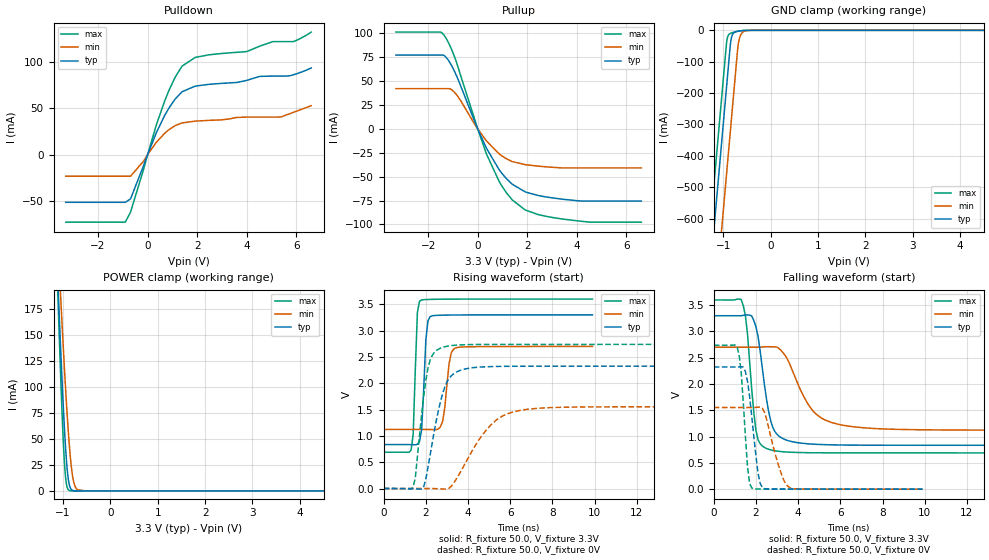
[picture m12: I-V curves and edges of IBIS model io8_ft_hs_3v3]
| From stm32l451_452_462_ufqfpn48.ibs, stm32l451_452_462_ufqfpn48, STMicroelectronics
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[Model]   io8_ft_hs_3v3
Model_type I/O
Polarity   Non-Inverting
Enable   Active-Low
| CAP_THRESHOLD on pad IOFT is "UDTCAPC" :
| Rising=30.00f vddiom   Falling=70.00f vddiom
| C_comp min and max val. don't necessarily correlate with the min and max pvt
| but are the smallest and greatest pad capacitance found.
| var   typ   min   max
C_comp   2.21487pF  2.18664pF  2.96105pF
|C_comp_pullup   1.17157pF  1.24175pF  1.62373pF
|C_comp_pulldown   1.04330pF  944.88729fF  1.33732pF
Vinl = 810.0mV
Vinh = 2.52V
Vmeas = 1.65V   | Reference voltage for timing measurements
Cref  = 50.0pF   | Timing specification test load capacitance value
Rref  = 100.0MOhm   | Timing specification test load resistance value
Vref  = 1.65V   | Timing specification test load voltage
[Model Spec]
| TIME_THRESHOLD on pin ZIV12 is "CMOS" :
| Rising=50.00f vdd   Falling=50.00f vdd
Vinl 1.34770V 1.11470V 1.44970V
Vinh 1.77530V 1.49030V 1.90330V
| variable   typ   min   max
[Temperature Range] 25.0 140.0 -40.0
| variable   typ   min   max
[Voltage Range] 3.3V 2.7V 3.6V
| variable   typ   min   max
[POWER Clamp Reference] 3.3V 2.7V 3.6V
| variable   typ   min   max
[GND Clamp Reference] 0V 0V 0V
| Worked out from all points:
|   slope of the pulldown table from 0 to 0.495 V, typ, clamps not added: 15.6 ohm
|   slope of the pullup table from 0 to 0.495 V, typ, clamps not added: 18.7 ohm
|   GND clamp passes 1 mA (typ) near -0.60 V on its own axis
|   POWER clamp passes 1 mA (typ) near -0.81 V on its own axis
|   rising waveform, R_fixture 50.0, V_fixture 3.3V: 20-80 % time 171ps typ, 248ps min, 150ps max; typ from 0.835 V to 3.3 V
|   falling waveform, R_fixture 50.0, V_fixture 3.3V: 20-80 % time 549ps typ, 1.23ns min, 374ps max; typ from 3.3 V to 0.835 V
|   rising waveform, R_fixture 50.0, V_fixture 0V: 20-80 % time 714ps typ, 1.53ns min, 476ps max; typ from 0 V to 2.33 V
|   falling waveform, R_fixture 50.0, V_fixture 0V: 20-80 % time 384ps typ, 630ps min, 273ps max; typ from 2.33 V to 0 V
[POWER Clamp]
-3.3V     2.991A     2.546A     3.694A
-1.11V    202.2mA    242.3mA    190.9mA
-1.09V    180mA      223.6mA    163.4mA
-1.05V    136.9mA    187mA      110.9mA
-1.01V    96.55mA    151.6mA    64.02mA
-970mV    60.39mA    117.9mA    27.41mA
-930mV    31.08mA    86.54mA    7.282mA
-860mV    4.779mA    40.5mA     315.2uA
-810mV    823.2uA    18.15mA    29.21uA
-750mV    88.98uA    4.952mA    1.667uA
-510mV    11.25nA    8.405uA    51.8pA
6.6V      0A         0A         0A
[GND Clamp]
-3.3V     -4.209A    -4.487A    -4.067A
-1.41V    -996.3mA   -1.274A    -854.3mA
-1.25V    -724.3mA   -1.002A    -582.3mA
-1.21V    -656.3mA   -933.6mA   -514.3mA
-930mV    -180.3mA   -457.6mA   -39.53mA
-900mV    -129.3mA   -406.6mA   -18.05mA
-840mV    -33.79mA   -304.6mA   -9.105mA
-790mV    -10.15mA   -219.6mA   -6.665mA
-680mV    -2.476mA   -41.57mA   -2.768mA
-630mV    -1.406mA   -13.77mA   -1.51mA
-530mV    -268.4uA   -1.762mA   -214.9uA
6.6V      833.9pA    196.4nA    597.5pA
| variable   typ   min   max
[Pullup Reference] 3.3V 2.7V 3.6V
| variable   typ   min   max
[Pulldown Reference] 0V 0V 0V
[Pullup]
-3.3V     77.35mA    42.24mA    101.4mA
-1.51V    77.35mA    42.24mA    101.4mA
-1.34V    76.54mA    42.24mA    97.42mA
-1.1V     68.45mA    41.76mA    85.85mA
-870mV    56.55mA    36.27mA    70.84mA
350mV     -20.12mA   -12.47mA   -26.09mA
860mV     -42.5mA    -25.9mA    -54.7mA
1.39V     -57.81mA   -34.14mA   -74.25mA
1.92V     -65.96mA   -37.41mA   -84.89mA
2.96V     -71.97mA   -40.03mA   -92.43mA
4.54V     -75.45mA   -40.79mA   -97.6mA
6.6V      -75.45mA   -40.79mA   -97.6mA
[Pulldown]
-3.3V     -51.64mA   -23.39mA   -73.18mA
-900mV    -51.64mA   -23.39mA   -73.04mA
-690mV    -47.97mA   -23.39mA   -62.4mA
350mV     23.63mA    13.27mA    31.99mA
690mV     42.49mA    23.17mA    58.21mA
1.12V     60.48mA    31.51mA    84.25mA
1.39V     68.1mA     34.34mA    95.86mA
1.92V     74.17mA    36.28mA    105.3mA
4V        80.41mA    40.64mA    111.6mA
5.39V     85.07mA    40.9mA     122.4mA
5.88V     86.5mA     45.8mA     122.4mA
6.6V      93.9mA     53mA       132.7mA
[Ramp]
dV/dt_r 1.39485V/710.6362ps 931.93155mV/1.53332ns 1.64323V/471.61496ps
dV/dt_f 1.47909V/543.0213ps 946.45147mV/1.22574ns 1.74617V/364.2076ps
R_load = 50.0
| Removed startup time: 0s 0s 0s  .
| Removed end time: 9.9ns.
[Rising Waveform]
R_fixture   = 50.0
V_fixture   = 3.3V
V_fixture_min = 2.7V
V_fixture_max = 3.6V
0s        834.8mV    1.123V     689.8mV
1.3ns     834.5mV    1.123V     730.3mV
1.4ns     834.1mV    1.123V     1.027V
1.6ns     838.8mV    1.123V     3.345V
1.7ns     893.4mV    1.123V     3.558V
2ns       2.824V     1.122V     3.591V
2.2ns     3.264V     1.121V     3.594V
2.8ns     3.294V     1.284V     3.598V
3.4ns     3.297V     2.67V      3.599V
9.9ns     3.3V       2.7V       3.6V
| Removed startup time: 0s 0s 0s  .
| Removed end time: 19.9ns.
[Falling Waveform]
R_fixture   = 50.0
V_fixture   = 3.3V
V_fixture_min = 2.7V
V_fixture_max = 3.6V
0s        3.3V       2.7V       3.6V
1.3ns     3.3V       2.7V       3.608V
1.6ns     3.315V     2.7V       2.945V
2ns       3.087V     2.7V       1.115V
2.6ns     1.481V     2.711V     758.7mV
2.9ns     1.093V     2.707V     730.4mV
3.3ns     958.1mV    2.589V     710.9mV
4.6ns     858.6mV    1.542V     693.1mV
5.9ns     840.3mV    1.234V     690.4mV
19.9ns    834.9mV    1.123V     689.8mV
| Removed startup time: 0s 0s 0s  .
| Removed end time: 19.9ns.
[Rising Waveform]
R_fixture   = 50.0
V_fixture   = 0V
V_fixture_min = 0V
V_fixture_max = 0V
0s        -11.66uV   -15.19uV   -4.074uV
1.4ns     305.9uV    210.4nV    28.85mV
1.5ns     -1.922mV   715.8nV    202mV
1.9ns     37.18mV    31.86uV    1.754V
2.1ns     396.8mV    98.36uV    2.282V
2.8ns     1.807V     -10.85mV   2.683V
3.6ns     2.241V     283.8mV    2.729V
5ns       2.316V     1.173V     2.738V
6.3ns     2.324V     1.47V      2.739V
19.9ns    2.325V     1.553V     2.739V
| Removed startup time: 0s 0s 0s  .
| Removed end time: 9.9ns.
[Falling Waveform]
R_fixture   = 50.0
V_fixture   = 0V
V_fixture_min = 0V
V_fixture_max = 0V
0s        2.325V     1.553V     2.739V
1.1ns     2.325V     1.553V     2.711V
1.3ns     2.33V      1.553V     2.226V
1.5ns     2.237V     1.553V     1.005V
1.6ns     2.054V     1.553V     422.8mV
1.8ns     1.386V     1.553V     21.65mV
2.1ns     300.6mV    1.56V      3.581mV
2.4ns     9.714mV    1.466V     2.303mV
3.6ns     1.358mV    29.89mV    659.1uV
9.9ns     23.5uV     100.6uV    9.443uV
